VERSION 5.7 ;
  NOWIREEXTENSIONATPIN ON ;
  DIVIDERCHAR "/" ;
  BUSBITCHARS "[]" ;
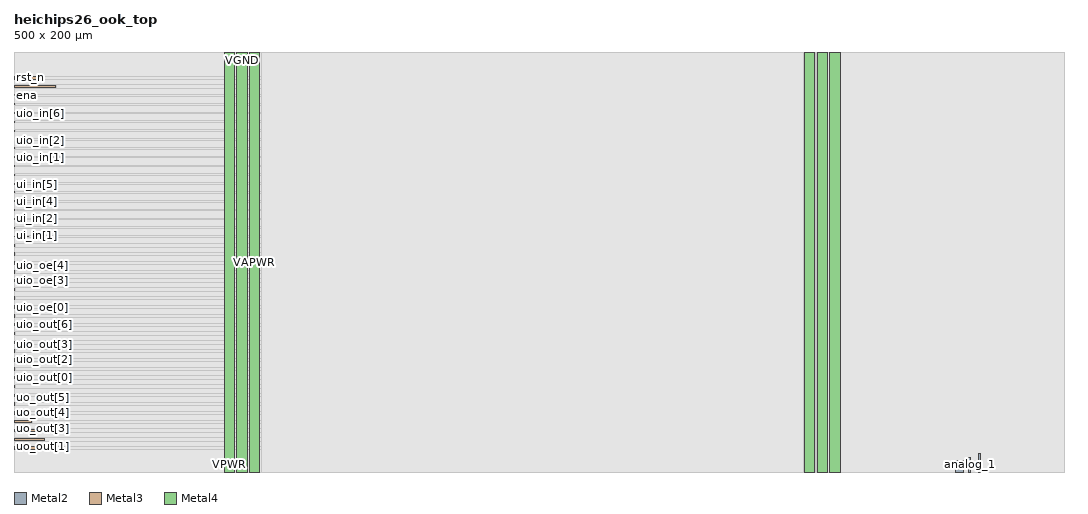
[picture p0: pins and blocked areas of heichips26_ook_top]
MACRO heichips26_ook_top
  CLASS BLOCK ;
  FOREIGN heichips26_ook_top ;
  ORIGIN 0.000 0.000 ;
  SIZE 500.000 BY 200.000 ;
  PIN analog_0
    DIRECTION INOUT ;
    USE SIGNAL ;
    ANTENNAGATEAREA 1.040000 ;
    ANTENNADIFFAREA 61.039997 ;
    PORT
      LAYER Metal2 ;
        RECT 448.240 0.000 452.240 5.350 ;
    END
  END analog_0
  PIN analog_1
    DIRECTION INOUT ;
    USE SIGNAL ;
    ANTENNAGATEAREA 42.000000 ;
    ANTENNADIFFAREA 4.400000 ;
    PORT
      LAYER Metal2 ;
        RECT 454.540 0.000 455.540 7.080 ;
    END
  END analog_1
  PIN analog_2
    DIRECTION INOUT ;
    USE SIGNAL ;
    ANTENNAGATEAREA 9.000000 ;
    PORT
      LAYER Metal2 ;
        RECT 459.240 0.000 460.440 8.800 ;
    END
  END analog_2
  PIN clk
    DIRECTION INPUT ;
    USE SIGNAL ;
    ANTENNAGATEAREA 1.450800 ;
    PORT
      LAYER Metal3 ;
        RECT 0.000 182.940 19.935 184.140 ;
    END
  END clk
  PIN ena
    DIRECTION INPUT ;
    USE SIGNAL ;
    PORT
      LAYER Metal3 ;
        RECT 0.000 179.140 0.400 179.540 ;
    END
  END ena
  PIN rst_n
    DIRECTION INPUT ;
    USE SIGNAL ;
    ANTENNAGATEAREA 0.180700 ;
    PORT
      LAYER Metal3 ;
        RECT 0.000 187.140 11.300 188.340 ;
    END
  END rst_n
  PIN ui_in[0]
    DIRECTION INPUT ;
    USE SIGNAL ;
    ANTENNAGATEAREA 0.180700 ;
    PORT
      LAYER Metal3 ;
        RECT 0.000 111.920 7.020 112.360 ;
    END
  END ui_in[0]
  PIN ui_in[1]
    DIRECTION INPUT ;
    USE SIGNAL ;
    PORT
      LAYER Metal3 ;
        RECT 0.000 116.140 0.400 116.540 ;
    END
  END ui_in[1]
  PIN ui_in[2]
    DIRECTION INPUT ;
    USE SIGNAL ;
    PORT
      LAYER Metal3 ;
        RECT 0.000 120.340 0.400 120.740 ;
    END
  END ui_in[2]
  PIN ui_in[3]
    DIRECTION INPUT ;
    USE SIGNAL ;
    PORT
      LAYER Metal3 ;
        RECT 0.000 124.540 0.400 124.940 ;
    END
  END ui_in[3]
  PIN ui_in[4]
    DIRECTION INPUT ;
    USE SIGNAL ;
    PORT
      LAYER Metal3 ;
        RECT 0.000 128.740 0.400 129.140 ;
    END
  END ui_in[4]
  PIN ui_in[5]
    DIRECTION INPUT ;
    USE SIGNAL ;
    PORT
      LAYER Metal3 ;
        RECT 0.000 132.940 0.400 133.340 ;
    END
  END ui_in[5]
  PIN ui_in[6]
    DIRECTION INPUT ;
    USE SIGNAL ;
    PORT
      LAYER Metal3 ;
        RECT 0.000 137.140 0.400 137.540 ;
    END
  END ui_in[6]
  PIN ui_in[7]
    DIRECTION INPUT ;
    USE SIGNAL ;
    PORT
      LAYER Metal3 ;
        RECT 0.000 141.340 0.400 141.740 ;
    END
  END ui_in[7]
  PIN uio_in[0]
    DIRECTION INPUT ;
    USE SIGNAL ;
    PORT
      LAYER Metal3 ;
        RECT 0.000 145.540 0.400 145.940 ;
    END
  END uio_in[0]
  PIN uio_in[1]
    DIRECTION INPUT ;
    USE SIGNAL ;
    PORT
      LAYER Metal3 ;
        RECT 0.000 149.740 0.400 150.140 ;
    END
  END uio_in[1]
  PIN uio_in[2]
    DIRECTION INPUT ;
    USE SIGNAL ;
    PORT
      LAYER Metal3 ;
        RECT 0.000 153.940 0.400 154.340 ;
    END
  END uio_in[2]
  PIN uio_in[3]
    DIRECTION INPUT ;
    USE SIGNAL ;
    PORT
      LAYER Metal3 ;
        RECT 0.000 158.140 0.400 158.540 ;
    END
  END uio_in[3]
  PIN uio_in[4]
    DIRECTION INPUT ;
    USE SIGNAL ;
    PORT
      LAYER Metal3 ;
        RECT 0.000 162.340 0.400 162.740 ;
    END
  END uio_in[4]
  PIN uio_in[5]
    DIRECTION INPUT ;
    USE SIGNAL ;
    PORT
      LAYER Metal3 ;
        RECT 0.000 166.540 0.400 166.940 ;
    END
  END uio_in[5]
  PIN uio_in[6]
    DIRECTION INPUT ;
    USE SIGNAL ;
    PORT
      LAYER Metal3 ;
        RECT 0.000 170.740 0.400 171.140 ;
    END
  END uio_in[6]
  PIN uio_in[7]
    DIRECTION INPUT ;
    USE SIGNAL ;
    PORT
      LAYER Metal3 ;
        RECT 0.000 174.940 0.400 175.340 ;
    END
  END uio_in[7]
  PIN uio_oe[0]
    DIRECTION OUTPUT ;
    USE SIGNAL ;
    PORT
      LAYER Metal3 ;
        RECT 0.000 77.940 0.475 79.140 ;
    END
  END uio_oe[0]
  PIN uio_oe[1]
    DIRECTION OUTPUT ;
    USE SIGNAL ;
    PORT
      LAYER Metal3 ;
        RECT 0.000 82.140 0.475 83.340 ;
    END
  END uio_oe[1]
  PIN uio_oe[2]
    DIRECTION OUTPUT ;
    USE SIGNAL ;
    PORT
      LAYER Metal3 ;
        RECT 0.000 86.340 0.475 87.540 ;
    END
  END uio_oe[2]
  PIN uio_oe[3]
    DIRECTION OUTPUT ;
    USE SIGNAL ;
    PORT
      LAYER Metal3 ;
        RECT 0.000 90.540 0.475 91.740 ;
    END
  END uio_oe[3]
  PIN uio_oe[4]
    DIRECTION OUTPUT ;
    USE SIGNAL ;
    PORT
      LAYER Metal3 ;
        RECT 0.000 94.740 0.475 95.940 ;
    END
  END uio_oe[4]
  PIN uio_oe[5]
    DIRECTION OUTPUT ;
    USE SIGNAL ;
    PORT
      LAYER Metal3 ;
        RECT 0.000 98.940 0.475 100.140 ;
    END
  END uio_oe[5]
  PIN uio_oe[6]
    DIRECTION OUTPUT ;
    USE SIGNAL ;
    PORT
      LAYER Metal3 ;
        RECT 0.000 103.140 0.475 104.340 ;
    END
  END uio_oe[6]
  PIN uio_oe[7]
    DIRECTION OUTPUT ;
    USE SIGNAL ;
    PORT
      LAYER Metal3 ;
        RECT 0.000 107.340 0.475 108.540 ;
    END
  END uio_oe[7]
  PIN uio_out[0]
    DIRECTION OUTPUT ;
    USE SIGNAL ;
    PORT
      LAYER Metal3 ;
        RECT 0.000 44.340 0.475 45.540 ;
    END
  END uio_out[0]
  PIN uio_out[1]
    DIRECTION OUTPUT ;
    USE SIGNAL ;
    PORT
      LAYER Metal3 ;
        RECT 0.000 48.540 0.475 49.740 ;
    END
  END uio_out[1]
  PIN uio_out[2]
    DIRECTION OUTPUT ;
    USE SIGNAL ;
    PORT
      LAYER Metal3 ;
        RECT 0.000 52.740 0.475 53.940 ;
    END
  END uio_out[2]
  PIN uio_out[3]
    DIRECTION OUTPUT ;
    USE SIGNAL ;
    PORT
      LAYER Metal3 ;
        RECT 0.000 56.940 0.475 58.140 ;
    END
  END uio_out[3]
  PIN uio_out[4]
    DIRECTION OUTPUT ;
    USE SIGNAL ;
    PORT
      LAYER Metal3 ;
        RECT 0.000 61.140 0.475 62.340 ;
    END
  END uio_out[4]
  PIN uio_out[5]
    DIRECTION OUTPUT ;
    USE SIGNAL ;
    PORT
      LAYER Metal3 ;
        RECT 0.000 65.340 0.475 66.540 ;
    END
  END uio_out[5]
  PIN uio_out[6]
    DIRECTION OUTPUT ;
    USE SIGNAL ;
    PORT
      LAYER Metal3 ;
        RECT 0.000 69.540 0.475 70.740 ;
    END
  END uio_out[6]
  PIN uio_out[7]
    DIRECTION OUTPUT ;
    USE SIGNAL ;
    PORT
      LAYER Metal3 ;
        RECT 0.000 73.740 0.475 74.940 ;
    END
  END uio_out[7]
  PIN uo_out[0]
    DIRECTION OUTPUT ;
    USE SIGNAL ;
    ANTENNADIFFAREA 0.708600 ;
    PORT
      LAYER Metal3 ;
        RECT 0.000 10.740 17.710 11.940 ;
    END
  END uo_out[0]
  PIN uo_out[1]
    DIRECTION OUTPUT ;
    USE SIGNAL ;
    ANTENNADIFFAREA 0.708600 ;
    PORT
      LAYER Metal3 ;
        RECT 0.000 14.940 14.550 16.140 ;
    END
  END uo_out[1]
  PIN uo_out[2]
    DIRECTION OUTPUT ;
    USE SIGNAL ;
    ANTENNADIFFAREA 0.708600 ;
    PORT
      LAYER Metal3 ;
        RECT 0.000 19.140 11.570 20.340 ;
    END
  END uo_out[2]
  PIN uo_out[3]
    DIRECTION OUTPUT ;
    USE SIGNAL ;
    ANTENNADIFFAREA 0.708600 ;
    PORT
      LAYER Metal3 ;
        RECT 0.000 23.340 8.560 24.540 ;
    END
  END uo_out[3]
  PIN uo_out[4]
    DIRECTION OUTPUT ;
    USE SIGNAL ;
    PORT
      LAYER Metal3 ;
        RECT 0.000 27.540 0.475 28.740 ;
    END
  END uo_out[4]
  PIN uo_out[5]
    DIRECTION OUTPUT ;
    USE SIGNAL ;
    PORT
      LAYER Metal3 ;
        RECT 0.000 31.740 0.475 32.940 ;
    END
  END uo_out[5]
  PIN uo_out[6]
    DIRECTION OUTPUT ;
    USE SIGNAL ;
    PORT
      LAYER Metal3 ;
        RECT 0.000 35.940 0.475 37.140 ;
    END
  END uo_out[6]
  PIN uo_out[7]
    DIRECTION OUTPUT ;
    USE SIGNAL ;
    PORT
      LAYER Metal3 ;
        RECT 0.000 40.140 0.475 41.340 ;
    END
  END uo_out[7]
  PIN VAPWR
    DIRECTION INOUT ;
    USE POWER ;
    PORT
      LAYER Metal4 ;
        RECT 112.000 0.000 117.000 200.000 ;
    END
    PORT
      LAYER Metal4 ;
        RECT 388.395 0.000 393.395 200.000 ;
    END
  END VAPWR
  PIN VGND
    DIRECTION INOUT ;
    USE GROUND ;
    PORT
      LAYER Metal4 ;
        RECT 106.000 0.000 111.000 200.000 ;
    END
    PORT
      LAYER Metal4 ;
        RECT 382.395 0.000 387.395 200.000 ;
    END
  END VGND
  PIN VPWR
    DIRECTION INOUT ;
    USE POWER ;
    PORT
      LAYER Metal4 ;
        RECT 100.000 0.000 105.000 200.000 ;
    END
    PORT
      LAYER Metal4 ;
        RECT 376.395 0.000 381.395 200.000 ;
    END
  END VPWR
  OBS
      LAYER GatPoly ;
        RECT 1.290 1.170 498.630 199.170 ;
      LAYER Metal1 ;
        RECT 0.000 1.170 498.630 199.170 ;
      LAYER Metal2 ;
        RECT 0.000 9.010 498.630 200.000 ;
        RECT 0.000 7.290 459.030 9.010 ;
        RECT 0.000 5.560 454.330 7.290 ;
        RECT 0.000 1.350 448.030 5.560 ;
        RECT 452.450 1.350 454.330 5.560 ;
        RECT 455.750 1.350 459.030 7.290 ;
        RECT 460.650 1.350 498.630 9.010 ;
      LAYER Metal3 ;
        RECT 0.475 188.550 499.970 200.000 ;
        RECT 11.510 186.930 499.970 188.550 ;
        RECT 0.475 184.350 499.970 186.930 ;
        RECT 20.145 182.730 499.970 184.350 ;
        RECT 0.475 179.750 499.970 182.730 ;
        RECT 0.610 178.930 499.970 179.750 ;
        RECT 0.475 175.550 499.970 178.930 ;
        RECT 0.610 174.730 499.970 175.550 ;
        RECT 0.475 171.350 499.970 174.730 ;
        RECT 0.610 170.530 499.970 171.350 ;
        RECT 0.475 167.150 499.970 170.530 ;
        RECT 0.610 166.330 499.970 167.150 ;
        RECT 0.475 162.950 499.970 166.330 ;
        RECT 0.610 162.130 499.970 162.950 ;
        RECT 0.475 158.750 499.970 162.130 ;
        RECT 0.610 157.930 499.970 158.750 ;
        RECT 0.475 154.550 499.970 157.930 ;
        RECT 0.610 153.730 499.970 154.550 ;
        RECT 0.475 150.350 499.970 153.730 ;
        RECT 0.610 149.530 499.970 150.350 ;
        RECT 0.475 146.150 499.970 149.530 ;
        RECT 0.610 145.330 499.970 146.150 ;
        RECT 0.475 141.950 499.970 145.330 ;
        RECT 0.610 141.130 499.970 141.950 ;
        RECT 0.475 137.750 499.970 141.130 ;
        RECT 0.610 136.930 499.970 137.750 ;
        RECT 0.475 133.550 499.970 136.930 ;
        RECT 0.610 132.730 499.970 133.550 ;
        RECT 0.475 129.350 499.970 132.730 ;
        RECT 0.610 128.530 499.970 129.350 ;
        RECT 0.475 125.150 499.970 128.530 ;
        RECT 0.610 124.330 499.970 125.150 ;
        RECT 0.475 120.950 499.970 124.330 ;
        RECT 0.610 120.130 499.970 120.950 ;
        RECT 0.475 116.750 499.970 120.130 ;
        RECT 0.610 115.930 499.970 116.750 ;
        RECT 0.475 112.570 499.970 115.930 ;
        RECT 7.230 111.710 499.970 112.570 ;
        RECT 0.475 108.750 499.970 111.710 ;
        RECT 0.685 107.130 499.970 108.750 ;
        RECT 0.475 104.550 499.970 107.130 ;
        RECT 0.685 102.930 499.970 104.550 ;
        RECT 0.475 100.350 499.970 102.930 ;
        RECT 0.685 98.730 499.970 100.350 ;
        RECT 0.475 96.150 499.970 98.730 ;
        RECT 0.685 94.530 499.970 96.150 ;
        RECT 0.475 91.950 499.970 94.530 ;
        RECT 0.685 90.330 499.970 91.950 ;
        RECT 0.475 87.750 499.970 90.330 ;
        RECT 0.685 86.130 499.970 87.750 ;
        RECT 0.475 83.550 499.970 86.130 ;
        RECT 0.685 81.930 499.970 83.550 ;
        RECT 0.475 79.350 499.970 81.930 ;
        RECT 0.685 77.730 499.970 79.350 ;
        RECT 0.475 75.150 499.970 77.730 ;
        RECT 0.685 73.530 499.970 75.150 ;
        RECT 0.475 70.950 499.970 73.530 ;
        RECT 0.685 69.330 499.970 70.950 ;
        RECT 0.475 66.750 499.970 69.330 ;
        RECT 0.685 65.130 499.970 66.750 ;
        RECT 0.475 62.550 499.970 65.130 ;
        RECT 0.685 60.930 499.970 62.550 ;
        RECT 0.475 58.350 499.970 60.930 ;
        RECT 0.685 56.730 499.970 58.350 ;
        RECT 0.475 54.150 499.970 56.730 ;
        RECT 0.685 52.530 499.970 54.150 ;
        RECT 0.475 49.950 499.970 52.530 ;
        RECT 0.685 48.330 499.970 49.950 ;
        RECT 0.475 45.750 499.970 48.330 ;
        RECT 0.685 44.130 499.970 45.750 ;
        RECT 0.475 41.550 499.970 44.130 ;
        RECT 0.685 39.930 499.970 41.550 ;
        RECT 0.475 37.350 499.970 39.930 ;
        RECT 0.685 35.730 499.970 37.350 ;
        RECT 0.475 33.150 499.970 35.730 ;
        RECT 0.685 31.530 499.970 33.150 ;
        RECT 0.475 28.950 499.970 31.530 ;
        RECT 0.685 27.330 499.970 28.950 ;
        RECT 0.475 24.750 499.970 27.330 ;
        RECT 8.770 23.130 499.970 24.750 ;
        RECT 0.475 20.550 499.970 23.130 ;
        RECT 11.780 18.930 499.970 20.550 ;
        RECT 0.475 16.350 499.970 18.930 ;
        RECT 14.760 14.730 499.970 16.350 ;
        RECT 0.475 12.150 499.970 14.730 ;
        RECT 17.920 10.530 499.970 12.150 ;
        RECT 0.475 0.000 499.970 10.530 ;
      LAYER Metal4 ;
        RECT 118.000 0.000 376.185 200.000 ;
        RECT 381.605 0.000 382.185 200.000 ;
        RECT 387.605 0.000 388.185 200.000 ;
        RECT 393.605 0.000 500.000 200.000 ;
  END
END heichips26_ook_top
END LIBRARY

